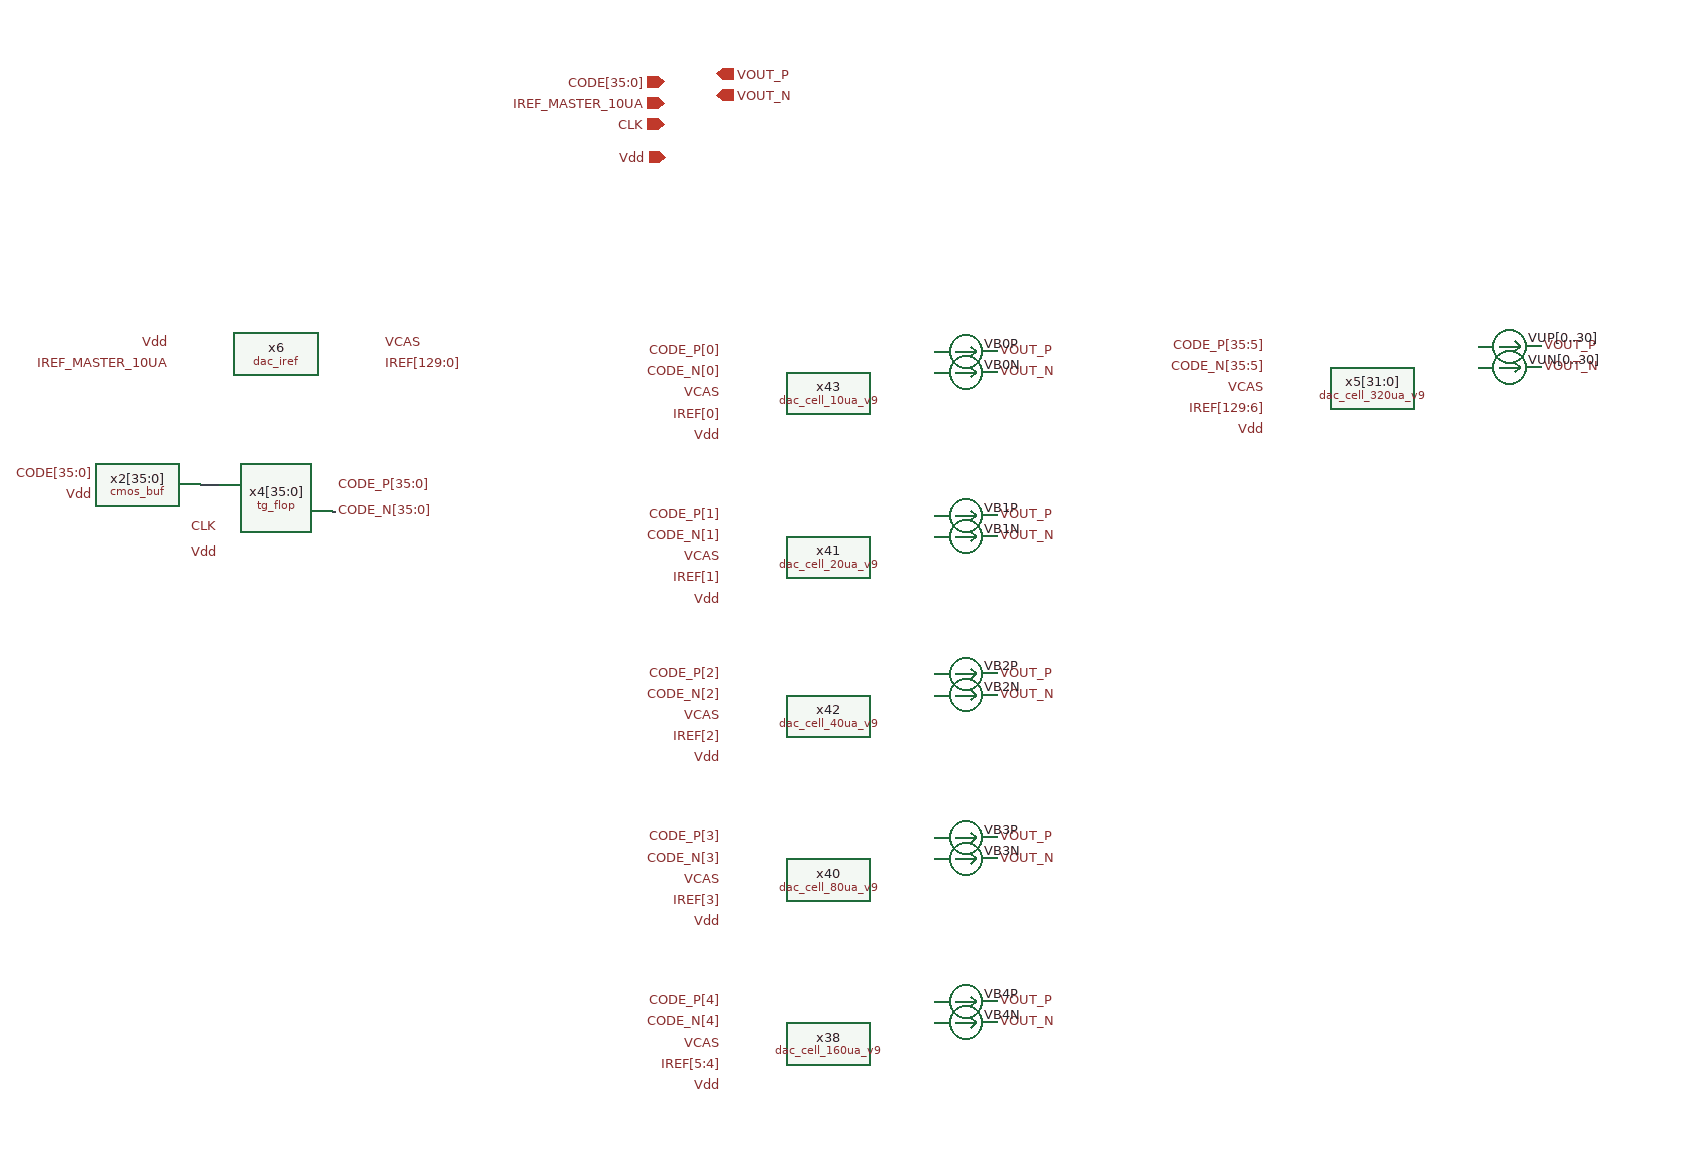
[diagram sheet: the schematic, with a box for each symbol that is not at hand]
v {xschem version=3.4.8RC file_version=1.3}
G {}
K {}
V {}
S {}
F {}
E {}
P 4 1 -68.75 542.5 {}
N -515 -15 -497.5 -15 {lab=#net1}
N -390 10 -387.5 10 {lab=CODE_N[35:0]}
C {lab_pin.sym} -21.25 318.75 2 1 {name=p293 sig_type=std_logic lab=CODE_P[3]}
C {lab_pin.sym} -21.25 338.75 2 1 {name=p294 sig_type=std_logic lab=CODE_N[3]}
C {lab_pin.sym} 493.125 -146.25 2 1 {name=p295 sig_type=std_logic lab=CODE_P[35:5]}
C {lab_pin.sym} 493.125 -126.25 2 1 {name=p296 sig_type=std_logic lab=CODE_N[35:5]}
C {lab_pin.sym} -21.25 493.75 2 1 {name=p297 sig_type=std_logic lab=CODE_N[4]}
C {lab_pin.sym} -21.25 163.75 2 1 {name=p298 sig_type=std_logic lab=CODE_P[2]}
C {lab_pin.sym} -21.25 183.75 2 1 {name=p299 sig_type=std_logic lab=CODE_N[2]}
C {lab_pin.sym} -21.25 13.75 2 1 {name=p300 sig_type=std_logic lab=CODE_P[1]}
C {lab_pin.sym} -21.25 33.75 2 1 {name=p301 sig_type=std_logic lab=CODE_N[1]}
C {lab_pin.sym} -21.25 473.75 2 1 {name=p302 sig_type=std_logic lab=CODE_P[4]}
C {lab_pin.sym} -21.25 -141.25 2 1 {name=p303 sig_type=std_logic lab=CODE_P[0]}
C {lab_pin.sym} -21.25 -121.25 2 1 {name=p304 sig_type=std_logic lab=CODE_N[0]}
C {cellv9/dac_cell_160ua_v9.sym} 78.75 513.75 0 0 {name=x38}
C {cellv9/dac_cell_80ua_v9.sym} 78.75 358.75 0 0 {name=x40}
C {cellv9/dac_cell_20ua_v9.sym} 78.75 53.75 0 0 {name=x41}
C {cellv9/dac_cell_40ua_v9.sym} 78.75 203.75 0 0 {name=x42}
C {cellv9/dac_cell_10ua_v9.sym} 78.75 -101.25 0 0 {name=x43}
C {lab_pin.sym} -21.25 -61.25 2 1 {name=p305 sig_type=std_logic lab=Vdd}
C {lab_pin.sym} -21.25 -81.25 2 1 {name=p306 sig_type=std_logic lab=IREF[0]}
C {lab_pin.sym} -21.25 -101.25 2 1 {name=p308 sig_type=std_logic lab=VCAS}
C {lab_pin.sym} -21.25 93.75 2 1 {name=p309 sig_type=std_logic lab=Vdd}
C {lab_pin.sym} -21.25 73.75 2 1 {name=p310 sig_type=std_logic lab=IREF[1]}
C {lab_pin.sym} -21.25 53.75 2 1 {name=p312 sig_type=std_logic lab=VCAS}
C {lab_pin.sym} -21.25 243.75 2 1 {name=p313 sig_type=std_logic lab=Vdd}
C {lab_pin.sym} -21.25 223.75 2 1 {name=p315 sig_type=std_logic lab=IREF[2]}
C {lab_pin.sym} -21.25 203.75 2 1 {name=p316 sig_type=std_logic lab=VCAS}
C {lab_pin.sym} -21.25 398.75 2 1 {name=p317 sig_type=std_logic lab=Vdd}
C {lab_pin.sym} -21.25 378.75 2 1 {name=p319 sig_type=std_logic lab=IREF[3]}
C {lab_pin.sym} -21.25 358.75 2 1 {name=p320 sig_type=std_logic lab=VCAS}
C {lab_pin.sym} -21.25 553.75 2 1 {name=p321 sig_type=std_logic lab=Vdd}
C {lab_pin.sym} -21.25 533.75 2 1 {name=p323 sig_type=std_logic lab=IREF[5:4]}
C {lab_pin.sym} -21.25 513.75 2 1 {name=p324 sig_type=std_logic lab=VCAS}
C {lab_pin.sym} 238.75 338.75 0 1 {name=p329 sig_type=std_logic lab=VOUT_N}
C {lab_pin.sym} 238.75 318.75 0 1 {name=p330 sig_type=std_logic lab=VOUT_P}
C {ammeter.sym} 208.75 318.75 3 0 {name=VB3P savecurrent=true spice_ignore=0}
C {ammeter.sym} 208.75 338.75 3 0 {name=VB3N savecurrent=true spice_ignore=0}
C {lab_pin.sym} 238.75 493.75 0 1 {name=p331 sig_type=std_logic lab=VOUT_N}
C {lab_pin.sym} 238.75 473.75 0 1 {name=p332 sig_type=std_logic lab=VOUT_P}
C {ammeter.sym} 208.75 473.75 3 0 {name=VB4P savecurrent=true spice_ignore=0}
C {ammeter.sym} 208.75 493.75 3 0 {name=VB4N savecurrent=true spice_ignore=0}
C {lab_pin.sym} 238.75 33.75 0 1 {name=p335 sig_type=std_logic lab=VOUT_N}
C {lab_pin.sym} 238.75 13.75 0 1 {name=p336 sig_type=std_logic lab=VOUT_P}
C {ammeter.sym} 208.75 13.75 3 0 {name=VB1P savecurrent=true spice_ignore=0}
C {ammeter.sym} 208.75 33.75 3 0 {name=VB1N savecurrent=true spice_ignore=0}
C {lab_pin.sym} 238.75 -121.25 0 1 {name=p337 sig_type=std_logic lab=VOUT_N}
C {lab_pin.sym} 238.75 -141.25 0 1 {name=p338 sig_type=std_logic lab=VOUT_P}
C {ammeter.sym} 208.75 -141.25 3 0 {name=VB0P savecurrent=true spice_ignore=0}
C {ammeter.sym} 208.75 -121.25 3 0 {name=VB0N savecurrent=true spice_ignore=0}
C {lab_pin.sym} 238.75 183.75 0 1 {name=p339 sig_type=std_logic lab=VOUT_N}
C {lab_pin.sym} 238.75 163.75 0 1 {name=p340 sig_type=std_logic lab=VOUT_P}
C {ammeter.sym} 208.75 163.75 3 0 {name=VB2P savecurrent=true spice_ignore=0}
C {ammeter.sym} 208.75 183.75 3 0 {name=VB2N savecurrent=true spice_ignore=0}
C {iref/dac_iref.sym} -443.75 -138.75 0 0 {name=x6}
C {lab_pin.sym} -543.75 -148.75 2 1 {name=p128 sig_type=std_logic lab=Vdd}
C {lab_pin.sym} -343.75 -148.75 0 1 {name=p129 sig_type=std_logic lab=VCAS}
C {lab_pin.sym} -343.75 -128.75 0 1 {name=p130 sig_type=std_logic lab=IREF[129:0]}
C {cellv9/dac_cell_320ua_v9.sym} 593.125 -106.25 0 0 {name=x5[31:0]}
C {lab_pin.sym} 493.125 -66.25 2 1 {name=p438 sig_type=std_logic lab=Vdd}
C {lab_pin.sym} 493.125 -86.25 2 1 {name=p440 sig_type=std_logic lab=IREF[129:6]}
C {lab_pin.sym} 493.125 -106.25 2 1 {name=p441 sig_type=std_logic lab=VCAS}
C {lab_pin.sym} 753.125 -126.25 0 1 {name=p132 sig_type=std_logic lab=VOUT_N}
C {lab_pin.sym} 753.125 -146.25 0 1 {name=p133 sig_type=std_logic lab=VOUT_P}
C {ammeter.sym} 723.125 -146.25 3 0 {name=VUP[0..30] savecurrent=true spice_ignore=0}
C {ammeter.sym} 723.125 -126.25 3 0 {name=VUN[0..30] savecurrent=true spice_ignore=0}
C {ipin.sym} -75 -325 0 0 {name=p1 lab=Vdd}
C {opin.sym} -27.5 -403.75 0 0 {name=p9 lab=VOUT_P}
C {ipin.sym} -76.25 -396.25 0 0 {name=p3 lab=CODE[35:0]}
C {opin.sym} -27.5 -383.75 0 0 {name=p4 lab=VOUT_N}
C {lab_pin.sym} -543.75 -128.75 0 0 {name=p12 sig_type=std_logic lab=IREF_MASTER_10UA}
C {ipin.sym} -76.25 -376.25 0 0 {name=p6 lab=IREF_MASTER_10UA}
C {common/cmos_buf.sym} -575 -5 0 0 {name=x2[35:0]}
C {lab_pin.sym} -615 -25 2 1 {name=p20 sig_type=std_logic lab=CODE[35:0]}
C {lab_pin.sym} -615 -5 2 1 {name=p21 sig_type=std_logic lab=Vdd}
C {common/tg_flop.sym} -442.5 20 0 0 {name=x4[35:0]}
C {lab_pin.sym} -497.5 50 2 1 {name=p5 sig_type=std_logic lab=Vdd}
C {lab_pin.sym} -387.5 -15 0 1 {name=p7 sig_type=std_logic lab=CODE_P[35:0]}
C {lab_pin.sym} -387.5 10 0 1 {name=p8 sig_type=std_logic lab=CODE_N[35:0]}
C {ipin.sym} -76.25 -356.25 0 0 {name=p2 lab=CLK}
C {lab_pin.sym} -497.5 25 2 1 {name=p10 sig_type=std_logic lab=CLK}
